VERSION 5.7 ;
BUSBITCHARS "[]" ;
DIVIDERCHAR "/" ;

# A subset of adjusted-gf180mcu_5LM_1TM_9K_9t_sc.lef from the OpenROAD-flow-
# scripts "gf180/aes-hybrid" design, reduced to the masters this test needs.
#
# gf180 is not a hybrid-row process, but ORFS uses it as a public proxy for one
# by alternating 9-track and 7-track rows.  The 9t cells as shipped carry a
# 0.9um power rail (+/-0.45um around the row boundary) while the 7t cells carry
# a 0.6um rail (+/-0.3um), so an unmodified 9t rail overhangs its 7t neighbour.
# The ORFS design therefore trims the 9t rails on the side that abuts a 7t row:
#
#   shipped  9t VSS  POLYGON 0 -0.45 0.56 -0.45 0.56 0.45 0 0.45  (0.90 tall)
#   adjusted 9t VSS  POLYGON 0 -0.3  0.56 -0.3  0.56 0.45 0 0.45  (0.75 tall)
#
# The adjusted rails are therefore *asymmetric about the row boundary*: they
# reach 0.45um into the 9t row and only 0.3um into the 7t row.  A followpin
# rail that is centred on the row boundary cannot describe that.
#
# Copyright 2022 GlobalFoundries PDK Authors
#
# Licensed under the Apache License, Version 2.0 (the "License");
# you may not use this file except in compliance with the License.
# You may obtain a copy of the License at
#
#      http://www.apache.org/licenses/LICENSE-2.0
#
# Unless required by applicable law or agreed to in writing, software
# distributed under the License is distributed on an "AS IS" BASIS,
# WITHOUT WARRANTIES OR CONDITIONS OF ANY KIND, either express or implied.
# See the License for the specific language governing permissions and
# limitations under the License.

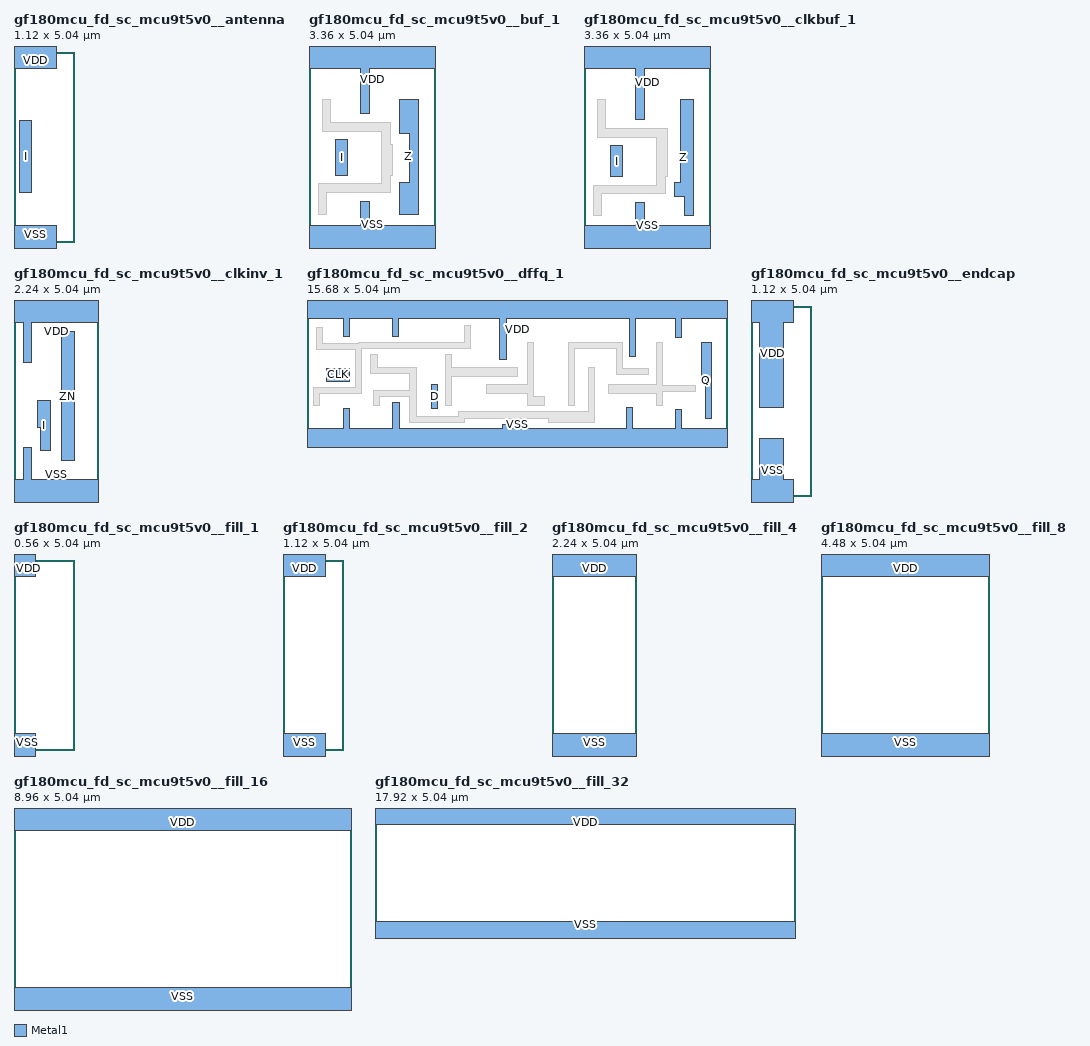
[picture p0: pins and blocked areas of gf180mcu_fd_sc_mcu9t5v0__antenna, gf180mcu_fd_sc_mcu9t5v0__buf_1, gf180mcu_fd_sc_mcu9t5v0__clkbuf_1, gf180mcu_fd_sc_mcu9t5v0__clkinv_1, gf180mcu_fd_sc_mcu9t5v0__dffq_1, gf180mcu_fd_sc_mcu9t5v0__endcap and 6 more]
MACRO gf180mcu_fd_sc_mcu9t5v0__antenna
  CLASS core ANTENNACELL ;
  FOREIGN gf180mcu_fd_sc_mcu9t5v0__antenna 0.0 0.0 ;
  ORIGIN 0 0 ;
  SYMMETRY X Y ;
  SITE GF018hv5v_green_sc9 ;
  SIZE 1.12 BY 5.04 ;
  PIN I
    DIRECTION INPUT ;
    ANTENNADIFFAREA 0.4068 ;
    PORT
      LAYER Metal1 ;
        POLYGON 0.15 1.315 0.475 1.315 0.475 3.215 0.15 3.215  ;
    END
  END I
  PIN VDD
    DIRECTION INOUT ;
    USE power ;
    SHAPE ABUTMENT ;
    PORT
      LAYER Metal1 ;
        POLYGON 0 4.59 1.12 4.59 1.12 5.34 0 5.34  ;
    END
  END VDD
  PIN VSS
    DIRECTION INOUT ;
    USE ground ;
    SHAPE ABUTMENT ;
    PORT
      LAYER Metal1 ;
        POLYGON 0 -0.3 1.12 -0.3 1.12 0.45 0 0.45  ;
    END
  END VSS
END gf180mcu_fd_sc_mcu9t5v0__antenna

MACRO gf180mcu_fd_sc_mcu9t5v0__buf_1
  CLASS core ;
  FOREIGN gf180mcu_fd_sc_mcu9t5v0__buf_1 0.0 0.0 ;
  ORIGIN 0 0 ;
  SYMMETRY X Y ;
  SITE GF018hv5v_green_sc9 ;
  SIZE 3.36 BY 5.04 ;
  PIN I
    DIRECTION INPUT ;
    ANTENNAGATEAREA 0.8535 ;
    PORT
      LAYER Metal1 ;
        POLYGON 0.71 1.77 1.015 1.77 1.015 2.71 0.71 2.71  ;
    END
  END I
  PIN Z
    DIRECTION OUTPUT ;
    ANTENNADIFFAREA 1.386 ;
    PORT
      LAYER Metal1 ;
        POLYGON 2.39 2.89 2.665 2.89 2.665 1.59 2.39 1.59 2.39 0.74 2.895 0.74 2.895 3.775 2.39 3.775  ;
    END
  END Z
  PIN VDD
    DIRECTION INOUT ;
    USE power ;
    SHAPE ABUTMENT ;
    PORT
      LAYER Metal1 ;
        POLYGON 0 4.59 1.365 4.59 1.365 3.4 1.595 3.4 1.595 4.59 2.215 4.59 3.36 4.59 3.36 5.34 2.215 5.34 0 5.34  ;
    END
  END VDD
  PIN VSS
    DIRECTION INOUT ;
    USE ground ;
    SHAPE ABUTMENT ;
    PORT
      LAYER Metal1 ;
        POLYGON 0 -0.3 3.36 -0.3 3.36 0.45 1.595 0.45 1.595 1.08 1.365 1.08 1.365 0.45 0 0.45  ;
    END
  END VSS
  OBS
      LAYER Metal1 ;
        POLYGON 0.345 2.94 1.93 2.94 1.93 1.54 0.245 1.54 0.245 0.74 0.475 0.74 0.475 1.31 2.16 1.31 2.16 1.775 2.215 1.775 2.215 2.585 2.16 2.585 2.16 3.17 0.575 3.17 0.575 3.775 0.345 3.775  ;
  END
END gf180mcu_fd_sc_mcu9t5v0__buf_1

MACRO gf180mcu_fd_sc_mcu9t5v0__clkbuf_1
  CLASS core ;
  FOREIGN gf180mcu_fd_sc_mcu9t5v0__clkbuf_1 0.0 0.0 ;
  ORIGIN 0 0 ;
  SYMMETRY X Y ;
  SITE GF018hv5v_green_sc9 ;
  SIZE 3.36 BY 5.04 ;
  PIN I
    DIRECTION INPUT ;
    ANTENNAGATEAREA 0.6765 ;
    PORT
      LAYER Metal1 ;
        POLYGON 0.71 1.74 1.015 1.74 1.015 2.55 0.71 2.55  ;
    END
  END I
  PIN Z
    DIRECTION OUTPUT ;
    ANTENNADIFFAREA 1.1572 ;
    PORT
      LAYER Metal1 ;
        POLYGON 2.39 1.21 2.665 1.21 2.665 0.71 2.895 0.71 2.895 3.775 2.565 3.775 2.565 1.59 2.39 1.59  ;
    END
  END Z
  PIN VDD
    DIRECTION INOUT ;
    USE power ;
    SHAPE ABUTMENT ;
    PORT
      LAYER Metal1 ;
        POLYGON 0 4.59 1.365 4.59 1.365 3.24 1.595 3.24 1.595 4.59 2.215 4.59 3.36 4.59 3.36 5.34 2.215 5.34 0 5.34  ;
    END
  END VDD
  PIN VSS
    DIRECTION INOUT ;
    USE ground ;
    SHAPE ABUTMENT ;
    PORT
      LAYER Metal1 ;
        POLYGON 0 -0.3 3.36 -0.3 3.36 0.45 1.595 0.45 1.595 1.05 1.365 1.05 1.365 0.45 0 0.45  ;
    END
  END VSS
  OBS
      LAYER Metal1 ;
        POLYGON 0.345 2.78 1.93 2.78 1.93 1.51 0.245 1.51 0.245 0.71 0.475 0.71 0.475 1.28 2.16 1.28 2.16 1.74 2.215 1.74 2.215 3.01 0.575 3.01 0.575 3.775 0.345 3.775  ;
  END
END gf180mcu_fd_sc_mcu9t5v0__clkbuf_1

MACRO gf180mcu_fd_sc_mcu9t5v0__clkinv_1
  CLASS core ;
  FOREIGN gf180mcu_fd_sc_mcu9t5v0__clkinv_1 0.0 0.0 ;
  ORIGIN 0 0 ;
  SYMMETRY X Y ;
  SITE GF018hv5v_green_sc9 ;
  SIZE 2.24 BY 5.04 ;
  PIN I
    DIRECTION INPUT ;
    ANTENNAGATEAREA 1.353 ;
    PORT
      LAYER Metal1 ;
        POLYGON 0.63 1.83 0.71 1.83 0.71 1.21 0.97 1.21 0.97 2.53 0.63 2.53  ;
    END
  END I
  PIN ZN
    DIRECTION OUTPUT ;
    ANTENNADIFFAREA 1.1264 ;
    PORT
      LAYER Metal1 ;
        POLYGON 1.265 0.945 1.595 0.945 1.595 4.36 1.265 4.36  ;
    END
  END ZN
  PIN VDD
    DIRECTION INOUT ;
    USE power ;
    SHAPE ABUTMENT ;
    PORT
      LAYER Metal1 ;
        POLYGON 0 4.59 0.245 4.59 0.245 3.55 0.475 3.55 0.475 4.59 2.24 4.59 2.24 5.34 0 5.34  ;
    END
  END VDD
  PIN VSS
    DIRECTION INOUT ;
    USE ground ;
    SHAPE ABUTMENT ;
    PORT
      LAYER Metal1 ;
        POLYGON 0 -0.3 2.24 -0.3 2.24 0.45 0.475 0.45 0.475 1.285 0.245 1.285 0.245 0.45 0 0.45  ;
    END
  END VSS
END gf180mcu_fd_sc_mcu9t5v0__clkinv_1

MACRO gf180mcu_fd_sc_mcu9t5v0__dffq_1
  CLASS core ;
  FOREIGN gf180mcu_fd_sc_mcu9t5v0__dffq_1 0.0 0.0 ;
  ORIGIN 0 0 ;
  SYMMETRY X Y ;
  SITE GF018hv5v_green_sc9 ;
  SIZE 15.68 BY 5.04 ;
  PIN D
    DIRECTION INPUT ;
    ANTENNAGATEAREA 0.848 ;
    PORT
      LAYER Metal1 ;
        POLYGON 4.63 1.21 4.89 1.21 4.89 2.115 4.63 2.115  ;
    END
  END D
  PIN CLK
    DIRECTION INPUT ;
    USE clock ;
    ANTENNAGATEAREA 1.164 ;
    PORT
      LAYER Metal1 ;
        POLYGON 0.71 2.235 1.575 2.235 1.575 2.71 0.71 2.71  ;
    END
  END CLK
  PIN Q
    DIRECTION OUTPUT ;
    ANTENNADIFFAREA 1.386 ;
    PORT
      LAYER Metal1 ;
        POLYGON 14.71 2.33 14.885 2.33 14.885 0.845 15.115 0.845 15.115 3.685 14.71 3.685  ;
    END
  END Q
  PIN VDD
    DIRECTION INOUT ;
    USE power ;
    SHAPE ABUTMENT ;
    PORT
      LAYER Metal1 ;
        POLYGON 0 4.59 1.365 4.59 1.365 3.895 1.595 3.895 1.595 4.59 3.185 4.59 3.185 3.905 3.415 3.905 3.415 4.59 6.115 4.59 7.205 4.59 7.205 3.045 7.435 3.045 7.435 4.59 7.875 4.59 8.855 4.59 12.025 4.59 12.025 3.145 12.255 3.145 12.255 4.59 12.75 4.59 13.765 4.59 13.765 3.875 13.995 3.875 13.995 4.59 14.49 4.59 15.68 4.59 15.68 5.34 14.49 5.34 12.75 5.34 8.855 5.34 7.875 5.34 6.115 5.34 0 5.34  ;
    END
  END VDD
  PIN VSS
    DIRECTION INOUT ;
    USE ground ;
    SHAPE ABUTMENT ;
    PORT
      LAYER Metal1 ;
        POLYGON 0 -0.3 15.68 -0.3 15.68 0.45 13.995 0.45 13.995 1.165 13.765 1.165 13.765 0.45 12.155 0.45 12.155 1.265 11.925 1.265 11.925 0.45 7.525 0.45 7.525 0.625 7.295 0.625 7.295 0.45 3.435 0.45 3.435 1.435 3.205 1.435 3.205 0.45 1.595 0.45 1.595 1.225 1.365 1.225 1.365 0.45 0 0.45  ;
    END
  END VSS
  OBS
      LAYER Metal1 ;
        POLYGON 0.345 3.425 1.805 3.425 1.805 2.005 0.245 2.005 0.245 1.315 0.475 1.315 0.475 1.775 2.035 1.775 2.035 3.445 6.115 3.445 6.115 4.315 5.885 4.315 5.885 3.675 1.94 3.675 1.94 3.655 0.575 3.655 0.575 4.235 0.345 4.235  ;
        POLYGON 5.165 1.315 5.395 1.315 5.395 2.415 7.875 2.415 7.875 2.755 5.395 2.755 5.395 3.215 5.165 3.215  ;
        POLYGON 6.685 1.775 8.225 1.775 8.225 1.315 8.855 1.315 8.855 1.655 8.455 1.655 8.455 3.685 8.225 3.685 8.225 2.115 6.685 2.115  ;
        POLYGON 2.385 2.525 3.845 2.525 3.845 1.895 2.485 1.895 2.485 1.315 2.715 1.315 2.715 1.665 3.845 1.665 3.845 0.69 5.89 0.69 5.89 0.855 9.01 0.855 9.01 0.69 10.735 0.69 10.735 2.755 10.505 2.755 10.505 1.085 5.665 1.085 5.665 0.92 4.075 0.92 4.075 2.755 2.615 2.755 2.615 3.215 2.385 3.215  ;
        POLYGON 9.745 1.315 9.975 1.315 9.975 3.455 11.565 3.455 11.565 2.47 12.75 2.47 12.75 2.7 11.795 2.7 11.795 3.685 9.745 3.685  ;
        POLYGON 11.265 1.775 13.045 1.775 13.045 1.315 13.275 1.315 13.275 1.83 14.49 1.83 14.49 2.06 13.275 2.06 13.275 3.685 13.045 3.685 13.045 2.115 11.265 2.115  ;
  END
END gf180mcu_fd_sc_mcu9t5v0__dffq_1

MACRO gf180mcu_fd_sc_mcu9t5v0__endcap
  CLASS ENDCAP PRE ;
  FOREIGN gf180mcu_fd_sc_mcu9t5v0__endcap 0.0 0.0 ;
  ORIGIN 0 0 ;
  SYMMETRY X Y ;
  SITE GF018hv5v_green_sc9 ;
  SIZE 1.12 BY 5.04 ;
  PIN VDD
    DIRECTION INOUT ;
    USE power ;
    SHAPE ABUTMENT ;
    PORT
      LAYER Metal1 ;
        POLYGON 0 4.59 0.23 4.59 0.23 2.34 0.85 2.34 0.85 4.59 1.12 4.59 1.12 5.34 0 5.34  ;
    END
  END VDD
  PIN VSS
    DIRECTION INOUT ;
    USE ground ;
    SHAPE ABUTMENT ;
    PORT
      LAYER Metal1 ;
        POLYGON 0 -0.3 1.12 -0.3 1.12 0.45 0.85 0.45 0.85 1.53 0.23 1.53 0.23 0.45 0 0.45  ;
    END
  END VSS
END gf180mcu_fd_sc_mcu9t5v0__endcap

MACRO gf180mcu_fd_sc_mcu9t5v0__fill_1
  CLASS core SPACER ;
  FOREIGN gf180mcu_fd_sc_mcu9t5v0__fill_1 0.0 0.0 ;
  ORIGIN 0 0 ;
  SYMMETRY X Y ;
  SITE GF018hv5v_green_sc9 ;
  SIZE 0.56 BY 5.04 ;
  PIN VDD
    DIRECTION INOUT ;
    USE power ;
    SHAPE ABUTMENT ;
    PORT
      LAYER Metal1 ;
        POLYGON 0 4.59 0.56 4.59 0.56 5.34 0 5.34  ;
    END
  END VDD
  PIN VSS
    DIRECTION INOUT ;
    USE ground ;
    SHAPE ABUTMENT ;
    PORT
      LAYER Metal1 ;
        POLYGON 0 -0.3 0.56 -0.3 0.56 0.45 0 0.45  ;
    END
  END VSS
END gf180mcu_fd_sc_mcu9t5v0__fill_1

MACRO gf180mcu_fd_sc_mcu9t5v0__fill_2
  CLASS core SPACER ;
  FOREIGN gf180mcu_fd_sc_mcu9t5v0__fill_2 0.0 0.0 ;
  ORIGIN 0 0 ;
  SYMMETRY X Y ;
  SITE GF018hv5v_green_sc9 ;
  SIZE 1.12 BY 5.04 ;
  PIN VDD
    DIRECTION INOUT ;
    USE power ;
    SHAPE ABUTMENT ;
    PORT
      LAYER Metal1 ;
        POLYGON 0 4.59 1.12 4.59 1.12 5.34 0 5.34  ;
    END
  END VDD
  PIN VSS
    DIRECTION INOUT ;
    USE ground ;
    SHAPE ABUTMENT ;
    PORT
      LAYER Metal1 ;
        POLYGON 0 -0.3 1.12 -0.3 1.12 0.45 0 0.45  ;
    END
  END VSS
END gf180mcu_fd_sc_mcu9t5v0__fill_2

MACRO gf180mcu_fd_sc_mcu9t5v0__fill_4
  CLASS core SPACER ;
  FOREIGN gf180mcu_fd_sc_mcu9t5v0__fill_4 0.0 0.0 ;
  ORIGIN 0 0 ;
  SYMMETRY X Y ;
  SITE GF018hv5v_green_sc9 ;
  SIZE 2.24 BY 5.04 ;
  PIN VDD
    DIRECTION INOUT ;
    USE power ;
    SHAPE ABUTMENT ;
    PORT
      LAYER Metal1 ;
        POLYGON 0 4.59 2.24 4.59 2.24 5.34 0 5.34  ;
    END
  END VDD
  PIN VSS
    DIRECTION INOUT ;
    USE ground ;
    SHAPE ABUTMENT ;
    PORT
      LAYER Metal1 ;
        POLYGON 0 -0.3 2.24 -0.3 2.24 0.45 0 0.45  ;
    END
  END VSS
END gf180mcu_fd_sc_mcu9t5v0__fill_4

MACRO gf180mcu_fd_sc_mcu9t5v0__fill_8
  CLASS core SPACER ;
  FOREIGN gf180mcu_fd_sc_mcu9t5v0__fill_8 0.0 0.0 ;
  ORIGIN 0 0 ;
  SYMMETRY X Y ;
  SITE GF018hv5v_green_sc9 ;
  SIZE 4.48 BY 5.04 ;
  PIN VDD
    DIRECTION INOUT ;
    USE power ;
    SHAPE ABUTMENT ;
    PORT
      LAYER Metal1 ;
        POLYGON 0 4.59 4.48 4.59 4.48 5.34 0 5.34  ;
    END
  END VDD
  PIN VSS
    DIRECTION INOUT ;
    USE ground ;
    SHAPE ABUTMENT ;
    PORT
      LAYER Metal1 ;
        POLYGON 0 -0.3 4.48 -0.3 4.48 0.45 0 0.45  ;
    END
  END VSS
END gf180mcu_fd_sc_mcu9t5v0__fill_8

MACRO gf180mcu_fd_sc_mcu9t5v0__fill_16
  CLASS core SPACER ;
  FOREIGN gf180mcu_fd_sc_mcu9t5v0__fill_16 0.0 0.0 ;
  ORIGIN 0 0 ;
  SYMMETRY X Y ;
  SITE GF018hv5v_green_sc9 ;
  SIZE 8.96 BY 5.04 ;
  PIN VDD
    DIRECTION INOUT ;
    USE power ;
    SHAPE ABUTMENT ;
    PORT
      LAYER Metal1 ;
        POLYGON 0 4.59 8.96 4.59 8.96 5.34 0 5.34  ;
    END
  END VDD
  PIN VSS
    DIRECTION INOUT ;
    USE ground ;
    SHAPE ABUTMENT ;
    PORT
      LAYER Metal1 ;
        POLYGON 0 -0.3 8.96 -0.3 8.96 0.45 0 0.45  ;
    END
  END VSS
END gf180mcu_fd_sc_mcu9t5v0__fill_16

MACRO gf180mcu_fd_sc_mcu9t5v0__fill_32
  CLASS core SPACER ;
  FOREIGN gf180mcu_fd_sc_mcu9t5v0__fill_32 0.0 0.0 ;
  ORIGIN 0 0 ;
  SYMMETRY X Y ;
  SITE GF018hv5v_green_sc9 ;
  SIZE 17.92 BY 5.04 ;
  PIN VDD
    DIRECTION INOUT ;
    USE power ;
    SHAPE ABUTMENT ;
    PORT
      LAYER Metal1 ;
        POLYGON 0 4.59 17.92 4.59 17.92 5.34 0 5.34  ;
    END
  END VDD
  PIN VSS
    DIRECTION INOUT ;
    USE ground ;
    SHAPE ABUTMENT ;
    PORT
      LAYER Metal1 ;
        POLYGON 0 -0.3 17.92 -0.3 17.92 0.45 0 0.45  ;
    END
  END VSS
END gf180mcu_fd_sc_mcu9t5v0__fill_32

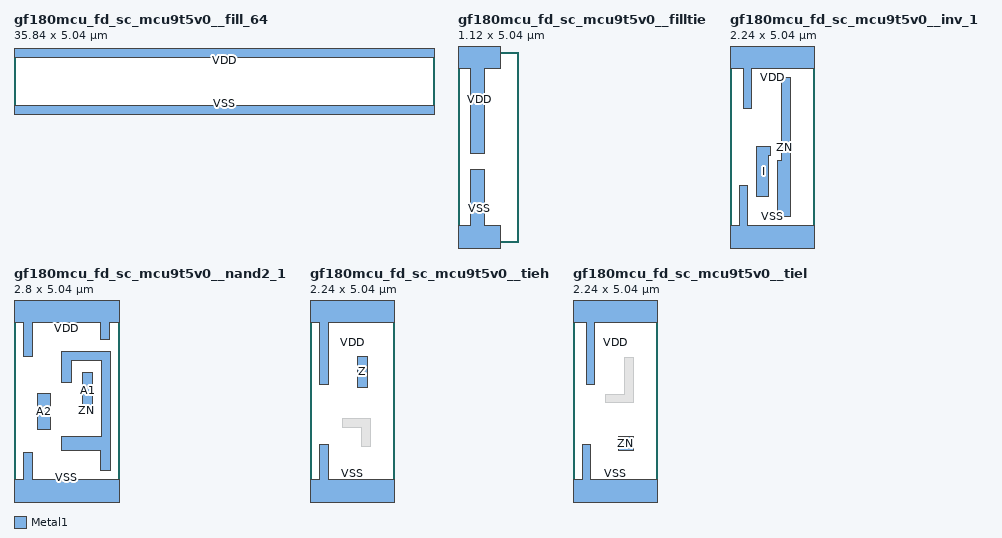
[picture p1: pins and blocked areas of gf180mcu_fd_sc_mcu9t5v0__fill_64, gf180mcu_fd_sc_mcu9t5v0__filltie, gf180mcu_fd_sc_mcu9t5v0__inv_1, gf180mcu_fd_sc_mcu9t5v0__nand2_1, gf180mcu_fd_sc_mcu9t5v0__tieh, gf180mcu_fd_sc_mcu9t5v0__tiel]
MACRO gf180mcu_fd_sc_mcu9t5v0__fill_64
  CLASS core SPACER ;
  FOREIGN gf180mcu_fd_sc_mcu9t5v0__fill_64 0.0 0.0 ;
  ORIGIN 0 0 ;
  SYMMETRY X Y ;
  SITE GF018hv5v_green_sc9 ;
  SIZE 35.84 BY 5.04 ;
  PIN VDD
    DIRECTION INOUT ;
    USE power ;
    SHAPE ABUTMENT ;
    PORT
      LAYER Metal1 ;
        POLYGON 0 4.59 35.84 4.59 35.84 5.34 0 5.34  ;
    END
  END VDD
  PIN VSS
    DIRECTION INOUT ;
    USE ground ;
    SHAPE ABUTMENT ;
    PORT
      LAYER Metal1 ;
        POLYGON 0 -0.3 35.84 -0.3 35.84 0.45 0 0.45  ;
    END
  END VSS
END gf180mcu_fd_sc_mcu9t5v0__fill_64

MACRO gf180mcu_fd_sc_mcu9t5v0__filltie
  CLASS core WELLTAP ;
  FOREIGN gf180mcu_fd_sc_mcu9t5v0__filltie 0.0 0.0 ;
  ORIGIN 0 0 ;
  SYMMETRY X Y ;
  SITE GF018hv5v_green_sc9 ;
  SIZE 1.12 BY 5.04 ;
  PIN VDD
    DIRECTION INOUT ;
    USE power ;
    SHAPE ABUTMENT ;
    PORT
      LAYER Metal1 ;
        POLYGON 0 4.59 0.33 4.59 0.33 2.34 0.71 2.34 0.71 4.59 1.12 4.59 1.12 5.34 0 5.34  ;
    END
  END VDD
  PIN VSS
    DIRECTION INOUT ;
    USE ground ;
    SHAPE ABUTMENT ;
    PORT
      LAYER Metal1 ;
        POLYGON 0 -0.3 1.12 -0.3 1.12 0.45 0.71 0.45 0.71 1.91 0.33 1.91 0.33 0.45 0 0.45  ;
    END
  END VSS
END gf180mcu_fd_sc_mcu9t5v0__filltie

MACRO gf180mcu_fd_sc_mcu9t5v0__inv_1
  CLASS core ;
  FOREIGN gf180mcu_fd_sc_mcu9t5v0__inv_1 0.0 0.0 ;
  ORIGIN 0 0 ;
  SYMMETRY X Y ;
  SITE GF018hv5v_green_sc9 ;
  SIZE 2.24 BY 5.04 ;
  PIN I
    DIRECTION INPUT ;
    ANTENNAGATEAREA 1.707 ;
    PORT
      LAYER Metal1 ;
        POLYGON 0.71 1.21 1.015 1.21 1.015 2.3 1.07 2.3 1.07 2.53 0.71 2.53  ;
    END
  END I
  PIN ZN
    DIRECTION OUTPUT ;
    ANTENNADIFFAREA 1.386 ;
    PORT
      LAYER Metal1 ;
        POLYGON 1.27 0.68 1.595 0.68 1.595 4.36 1.365 4.36 1.365 2.15 1.27 2.15  ;
    END
  END ZN
  PIN VDD
    DIRECTION INOUT ;
    USE power ;
    SHAPE ABUTMENT ;
    PORT
      LAYER Metal1 ;
        POLYGON 0 4.59 0.345 4.59 0.345 3.55 0.575 3.55 0.575 4.59 2.24 4.59 2.24 5.34 0 5.34  ;
    END
  END VDD
  PIN VSS
    DIRECTION INOUT ;
    USE ground ;
    SHAPE ABUTMENT ;
    PORT
      LAYER Metal1 ;
        POLYGON 0 -0.3 2.24 -0.3 2.24 0.45 0.475 0.45 0.475 1.49 0.245 1.49 0.245 0.45 0 0.45  ;
    END
  END VSS
END gf180mcu_fd_sc_mcu9t5v0__inv_1

MACRO gf180mcu_fd_sc_mcu9t5v0__nand2_1
  CLASS core ;
  FOREIGN gf180mcu_fd_sc_mcu9t5v0__nand2_1 0.0 0.0 ;
  ORIGIN 0 0 ;
  SYMMETRY X Y ;
  SITE GF018hv5v_green_sc9 ;
  SIZE 2.8 BY 5.04 ;
  PIN A1
    DIRECTION INPUT ;
    ANTENNAGATEAREA 1.6145 ;
    PORT
      LAYER Metal1 ;
        POLYGON 1.83 2.33 2.09 2.33 2.09 3.27 1.83 3.27  ;
    END
  END A1
  PIN A2
    DIRECTION INPUT ;
    ANTENNAGATEAREA 1.6145 ;
    PORT
      LAYER Metal1 ;
        POLYGON 0.635 1.77 0.975 1.77 0.975 2.71 0.635 2.71  ;
    END
  END A2
  PIN ZN
    DIRECTION OUTPUT ;
    ANTENNADIFFAREA 1.4362 ;
    PORT
      LAYER Metal1 ;
        POLYGON 1.27 3.02 1.53 3.02 1.53 3.6 2.32 3.6 2.32 1.59 1.27 1.59 1.27 1.21 2.29 1.21 2.29 0.68 2.55 0.68 2.55 3.83 1.27 3.83  ;
    END
  END ZN
  PIN VDD
    DIRECTION INOUT ;
    USE power ;
    SHAPE ABUTMENT ;
    PORT
      LAYER Metal1 ;
        POLYGON 0 4.59 0.25 4.59 0.25 3.69 0.48 3.69 0.48 4.59 2.29 4.59 2.29 4.16 2.52 4.16 2.52 4.59 2.8 4.59 2.8 5.34 0 5.34  ;
    END
  END VDD
  PIN VSS
    DIRECTION INOUT ;
    USE ground ;
    SHAPE ABUTMENT ;
    PORT
      LAYER Metal1 ;
        POLYGON 0 -0.3 2.8 -0.3 2.8 0.45 0.48 0.45 0.48 1.165 0.25 1.165 0.25 0.45 0 0.45  ;
    END
  END VSS
END gf180mcu_fd_sc_mcu9t5v0__nand2_1

MACRO gf180mcu_fd_sc_mcu9t5v0__tieh
  CLASS core TIEHIGH ;
  FOREIGN gf180mcu_fd_sc_mcu9t5v0__tieh 0.0 0.0 ;
  ORIGIN 0 0 ;
  SYMMETRY X Y ;
  SITE GF018hv5v_green_sc9 ;
  SIZE 2.24 BY 5.04 ;
  PIN Z
    DIRECTION OUTPUT ;
    ANTENNADIFFAREA 0.396 ;
    PORT
      LAYER Metal1 ;
        POLYGON 1.27 2.89 1.53 2.89 1.53 3.7 1.27 3.7  ;
    END
  END Z
  PIN VDD
    DIRECTION INOUT ;
    USE power ;
    SHAPE ABUTMENT ;
    PORT
      LAYER Metal1 ;
        POLYGON 0 4.59 0.25 4.59 0.25 2.945 0.48 2.945 0.48 4.59 1.6 4.59 2.24 4.59 2.24 5.34 1.6 5.34 0 5.34  ;
    END
  END VDD
  PIN VSS
    DIRECTION INOUT ;
    USE ground ;
    SHAPE ABUTMENT ;
    PORT
      LAYER Metal1 ;
        POLYGON 0 -0.3 2.24 -0.3 2.24 0.45 0.48 0.45 0.48 1.355 0.25 1.355 0.25 0.45 0 0.45  ;
    END
  END VSS
  OBS
      LAYER Metal1 ;
        POLYGON 0.875 1.83 1.37 1.83 1.37 1.315 1.6 1.315 1.6 2.06 0.875 2.06  ;
  END
END gf180mcu_fd_sc_mcu9t5v0__tieh

MACRO gf180mcu_fd_sc_mcu9t5v0__tiel
  CLASS core TIELOW ;
  FOREIGN gf180mcu_fd_sc_mcu9t5v0__tiel 0.0 0.0 ;
  ORIGIN 0 0 ;
  SYMMETRY X Y ;
  SITE GF018hv5v_green_sc9 ;
  SIZE 2.24 BY 5.04 ;
  PIN ZN
    DIRECTION OUTPUT ;
    ANTENNADIFFAREA 0.2904 ;
    PORT
      LAYER Metal1 ;
        POLYGON 1.215 1.21 1.595 1.21 1.595 1.59 1.215 1.59  ;
    END
  END ZN
  PIN VDD
    DIRECTION INOUT ;
    USE power ;
    SHAPE ABUTMENT ;
    PORT
      LAYER Metal1 ;
        POLYGON 0 4.59 0.345 4.59 0.345 2.945 0.575 2.945 0.575 4.59 1.595 4.59 2.24 4.59 2.24 5.34 1.595 5.34 0 5.34  ;
    END
  END VDD
  PIN VSS
    DIRECTION INOUT ;
    USE ground ;
    SHAPE ABUTMENT ;
    PORT
      LAYER Metal1 ;
        POLYGON 0 -0.3 2.24 -0.3 2.24 0.45 0.475 0.45 0.475 1.355 0.245 1.355 0.245 0.45 0 0.45  ;
    END
  END VSS
  OBS
      LAYER Metal1 ;
        POLYGON 0.87 2.47 1.595 2.47 1.595 3.685 1.365 3.685 1.365 2.7 0.87 2.7  ;
  END
END gf180mcu_fd_sc_mcu9t5v0__tiel

END LIBRARY
